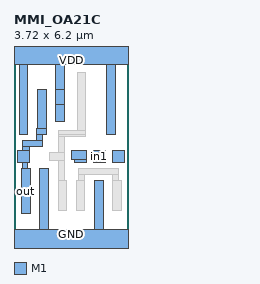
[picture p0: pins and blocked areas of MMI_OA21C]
MACRO MMI_OA21C
	CLASS CORE ;
	FOREIGN MMI_OA21C 0 0 ;
	SIZE 3.72 BY 6.2 ;
	SYMMETRY X Y ;
	SITE CORE1 ;
	PIN out
		DIRECTION output ;
		USE SIGNAL ;
		PORT
			LAYER M1 ;
			RECT 0.765 3.705 1.045 4.985 ;
			LAYER M1 ;
			RECT 0.75 3.515 1.045 3.705 ;
			LAYER M1 ;
			RECT 0.75 3.3 0.945 3.515 ;
			LAYER M1 ;
			RECT 0.265 3.11 0.945 3.3 ;
			LAYER M1 ;
			RECT 0.265 2.98 0.5 3.11 ;
			LAYER M1 ;
			RECT 0.12 2.6 0.5 2.98 ;
			LAYER M1 ;
			RECT 0.265 2.385 0.455 2.6 ;
			LAYER M1 ;
			RECT 0.245 0.915 0.525 2.385 ;
		END
		AntennaDiffArea 1.2859 ;
	END out
	PIN in1
		DIRECTION input ;
		USE SIGNAL ;
		PORT
			LAYER M1 ;
			RECT 2.6 2.925 2.98 2.98 ;
			LAYER M1 ;
			RECT 2.58 2.645 2.98 2.925 ;
			LAYER M1 ;
			RECT 2.6 2.6 2.98 2.645 ;
		END
		AntennaGateArea 0.468 ;
	END in1
	PIN GND
		DIRECTION inout ;
		USE GROUND ;
		PORT
			LAYER M1 ;
			RECT 0.835 0.42 1.115 2.385 ;
			LAYER M1 ;
			RECT 2.625 0.42 2.905 2 ;
			LAYER M1 ;
			RECT 0 -0.42 3.72 0.42 ;
		END
	END GND
	PIN in2
		DIRECTION input ;
		USE SIGNAL ;
		PORT
			LAYER M1 ;
			RECT 3.22 2.6 3.6 2.98 ;
		END
		AntennaGateArea 0.468 ;
	END in2
	PIN VDD
		DIRECTION inout ;
		USE POWER ;
		PORT
			LAYER M1 ;
			RECT 0 5.78 3.72 6.62 ;
			LAYER M1 ;
			RECT 0.175 3.515 0.455 5.78 ;
			LAYER M1 ;
			RECT 1.36 4.985 1.64 5.78 ;
			LAYER M1 ;
			RECT 1.355 4.485 1.64 4.985 ;
			LAYER M1 ;
			RECT 1.355 3.925 1.635 4.485 ;
			LAYER M1 ;
			RECT 3.025 3.515 3.305 5.78 ;
		END
	END VDD
	PIN in0
		DIRECTION input ;
		USE SIGNAL ;
		PORT
			LAYER M1 ;
			RECT 1.98 2.975 2.36 2.98 ;
			LAYER M1 ;
			RECT 1.875 2.695 2.36 2.975 ;
			LAYER M1 ;
			RECT 1.98 2.6 2.36 2.695 ;
		END
		AntennaGateArea 0.312 ;
	END in0
	OBS
		LAYER M1 ;
		RECT 2.065 3.64 2.345 5.525 ;
		LAYER M1 ;
		RECT 1.445 3.515 2.345 3.64 ;
		LAYER M1 ;
		RECT 1.445 3.45 2.34 3.515 ;
		LAYER M1 ;
		RECT 1.445 2.93 1.635 3.45 ;
		LAYER M1 ;
		RECT 1.165 2.65 1.635 2.93 ;
		LAYER M1 ;
		RECT 1.445 2 1.635 2.65 ;
		LAYER M1 ;
		RECT 2.12 2.205 3.41 2.4 ;
		LAYER M1 ;
		RECT 2.12 2 2.315 2.205 ;
		LAYER M1 ;
		RECT 3.22 2 3.41 2.205 ;
		LAYER M1 ;
		RECT 1.445 1.03 1.725 2 ;
		LAYER M1 ;
		RECT 2.035 1.03 2.315 2 ;
		LAYER M1 ;
		RECT 3.215 1.03 3.495 2 ;
	END
END MMI_OA21C
